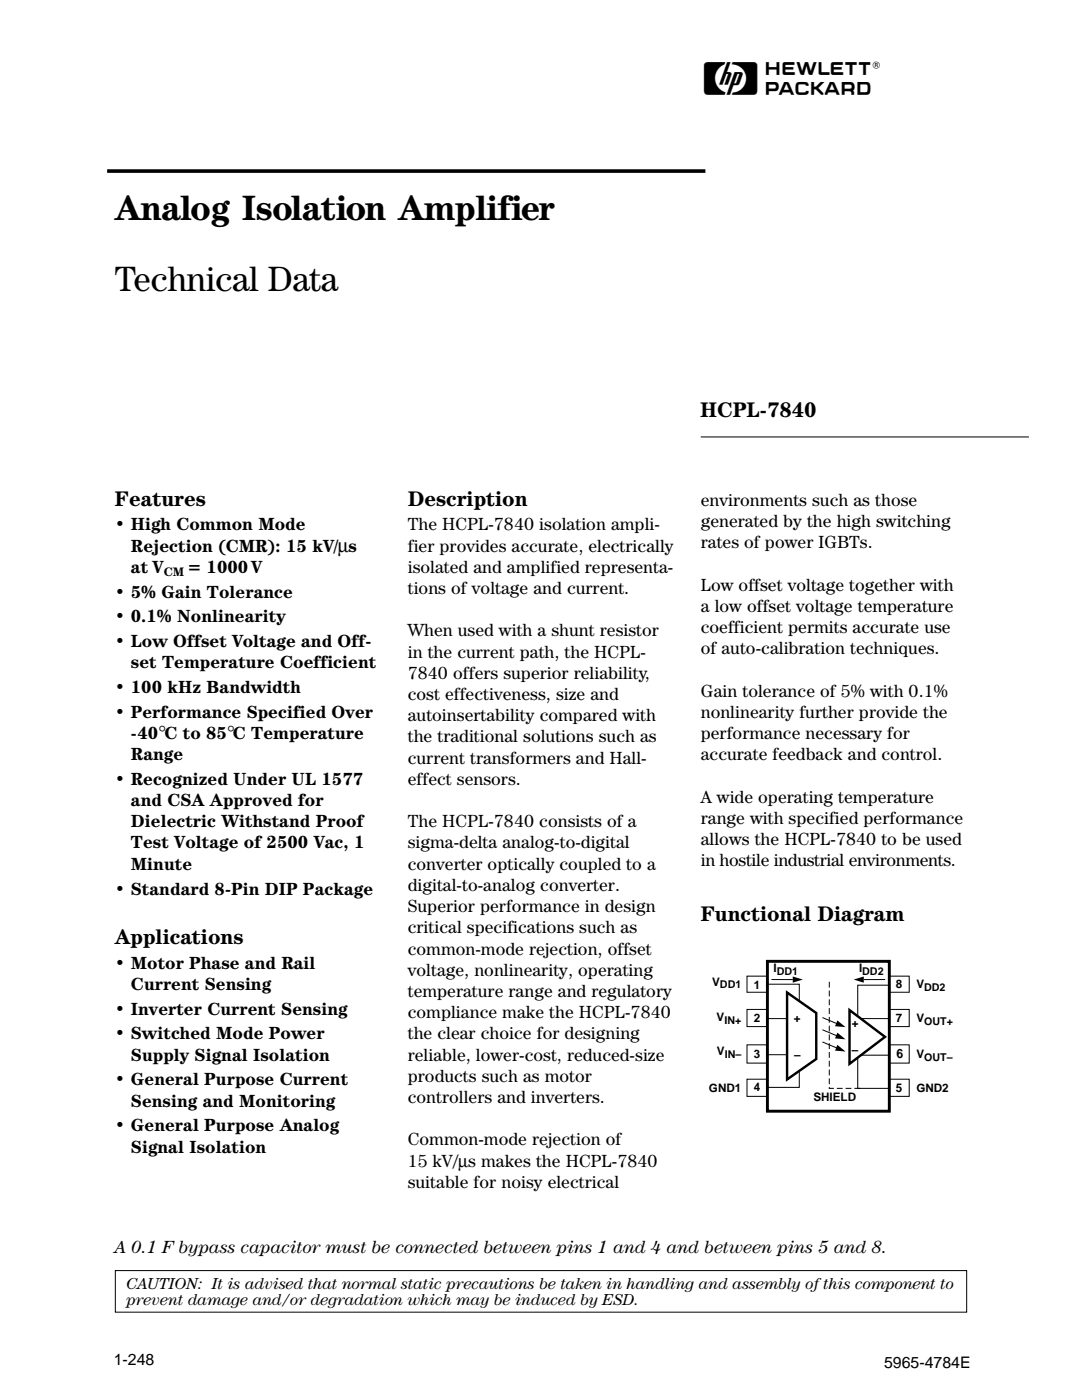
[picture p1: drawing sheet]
<svg xmlns="http://www.w3.org/2000/svg" width="216mm" height="279mm" viewBox="0 0 216 279" stroke-linecap="round" stroke-linejoin="round" font-family="sans-serif">
<defs><g id="words">
<g font-size="7.1">
<text x="139.9" y="17.8">H</text>
<text x="22.9" y="43.9">Analog Isolation Amplifier</text>
<text x="22.9" y="58">Technical Data</text>
</g>
<g font-size="4.2">
<text x="139.7" y="83.3">HCPL-7840</text>
<text x="22.9" y="100.9">Features</text>
<text x="81.4" y="100.9">Description</text>
<text x="139.8" y="183.8">Functional Diagram</text>
<text x="22.9" y="188.4">Applications</text>
</g>
<g font-size="3.5">
<text x="139.8" y="100.9">environments such as those</text>
<text x="22.9" y="105.8">• High Common Mode</text>
<text x="81.4" y="105.8">The HCPL-7840 isolation ampli-</text>
<text x="139.8" y="105.2">generated by the high switching</text>
<text x="26.1" y="110.1">Rejection (CMR): 15 kV/µs</text>
<text x="81.4" y="110.1">fier provides accurate, electrically</text>
<text x="139.8" y="109.4">rates of power IGBTs.</text>
<text x="22.9" y="119.3">• 5% Gain Tolerance</text>
<text x="26.1" y="114.3">at V</text>
<text x="37.4" y="114.3">= 1000 V</text>
<text x="81.4" y="114.3">isolated and amplified representa-</text>
<text x="81.4" y="118.5">tions of voltage and current.</text>
<text x="139.8" y="117.9">Low offset voltage together with</text>
<text x="22.9" y="124.2">• 0.1% Nonlinearity</text>
<text x="139.8" y="122.1">a low offset voltage temperature</text>
<text x="22.9" y="129.1">• Low Offset Voltage and Off-</text>
<text x="81.4" y="127">When used with a shunt resistor</text>
<text x="81.4" y="131.2">in the current path, the HCPL-</text>
<text x="139.8" y="126.3">coefficient permits accurate use</text>
<text x="139.8" y="130.6">of auto-calibration techniques.</text>
<text x="26.1" y="133.3">set Temperature Coefficient</text>
<text x="81.4" y="135.5">7840 offers superior reliability,</text>
<text x="22.9" y="138.3">• 100 kHz Bandwidth</text>
<text x="22.9" y="143.3">• Performance Specified Over</text>
<text x="81.4" y="139.7">cost effectiveness, size and</text>
<text x="81.4" y="143.9">autoinsertability compared with</text>
<text x="139.8" y="139">Gain tolerance of 5% with 0.1%</text>
<text x="139.8" y="143.3">nonlinearity further provide the</text>
<text x="26.1" y="147.5">-40°C to 85°C Temperature</text>
<text x="81.4" y="148.2">the traditional solutions such as</text>
<text x="139.8" y="147.5">performance necessary for</text>
<text x="26.1" y="151.7">Range</text>
<text x="81.4" y="152.4">current transformers and Hall-</text>
<text x="139.8" y="151.7">accurate feedback and control.</text>
<text x="22.9" y="156.6">• Recognized Under UL 1577</text>
<text x="26.1" y="160.9">and CSA Approved for</text>
<text x="81.4" y="156.6">effect sensors.</text>
<text x="139.8" y="160.2">A wide operating temperature</text>
<text x="26.1" y="165.1">Dielectric Withstand Proof</text>
<text x="81.4" y="165.1">The HCPL-7840 consists of a</text>
<text x="139.8" y="164.4">range with specified performance</text>
<text x="26.1" y="169.3">Test Voltage of 2500 Vac, 1</text>
<text x="26.1" y="173.6">Minute</text>
<text x="81.4" y="169.3">sigma-delta analog-to-digital</text>
<text x="81.4" y="173.6">converter optically coupled to a</text>
<text x="139.8" y="168.7">allows the HCPL-7840 to be used</text>
<text x="139.8" y="172.9">in hostile industrial environments.</text>
<text x="22.9" y="178.5">• Standard 8-Pin DIP Package</text>
<text x="81.4" y="177.8">digital-to-analog converter.</text>
<text x="81.4" y="182">Superior performance in design</text>
<text x="81.4" y="186.3">critical specifications such as</text>
<text x="81.4" y="190.5">common-mode rejection, offset</text>
<text x="22.9" y="193.3">• Motor Phase and Rail</text>
<text x="26.1" y="197.6">Current Sensing</text>
<text x="81.4" y="194.7">voltage, nonlinearity, operating</text>
<text x="22.9" y="202.5">• Inverter Current Sensing</text>
<text x="81.4" y="199">temperature range and regulatory</text>
<text x="81.4" y="203.2">compliance make the HCPL-7840</text>
<text x="22.9" y="207.4">• Switched Mode Power</text>
<text x="81.4" y="207.4">the clear choice for designing</text>
<text x="26.1" y="211.7">Supply Signal Isolation</text>
<text x="81.4" y="211.7">reliable, lower-cost, reduced-size</text>
<text x="81.4" y="215.9">products such as motor</text>
<text x="22.9" y="216.6">• General Purpose Current</text>
<text x="26.1" y="220.9">Sensing and Monitoring</text>
<text x="81.4" y="220.1">controllers and inverters.</text>
<text x="22.9" y="225.8">• General Purpose Analog</text>
<text x="26.1" y="230">Signal Isolation</text>
<text x="81.4" y="228.6">Common-mode rejection of</text>
<text x="81.4" y="232.8">15 kV/µs makes the HCPL-7840</text>
<text x="81.4" y="237.1">suitable for noisy electrical</text>
<text x="22.9" y="250.1">A 0.1 F bypass capacitor must be connected between pins 1 and 4 and between pins 5 and 8.</text>
</g>
<g font-size="3.2">
<text x="25.2" y="257.3">CAUTION: It is advised that normal static precautions be taken in handling and assembly of this component to</text>
<text x="25.2" y="260.4">prevent damage and/or degradation which may be induced by ESD.</text>
<text x="22.7" y="272.5">1-248</text>
<text x="176.4" y="272.9">5965-4784E</text>
</g>
<text font-size="2.6" x="178.9" y="211.2">6</text>
<text font-size="2.5" x="32.7" y="115">CM</text>
<g font-size="2.3">
<text x="142.1" y="196.7">V</text>
<text x="150.4" y="197.3">1</text>
<text x="154.3" y="194">I</text>
<text x="171.4" y="194">I</text>
<text x="178.8" y="197.1">8</text>
<text x="182.9" y="197.2">V</text>
<text x="143" y="203.7">V</text>
<text x="150.4" y="203.9">2</text>
<text x="178.8" y="203.9">7</text>
<text x="182.9" y="204">V</text>
<text x="158.4" y="204">+</text>
<text x="170" y="204.9">+</text>
<text x="143.1" y="210.6">V</text>
<text x="150.4" y="211.1">3</text>
<text x="158.4" y="211.3">–</text>
<text x="170" y="210.4">–</text>
<text x="182.9" y="211.2">V</text>
<text x="141.5" y="217.9">GND1</text>
<text x="150.4" y="217.7">4</text>
<text x="162.3" y="219.8">SHIELD</text>
<text x="178.8" y="217.9">5</text>
<text x="182.9" y="217.9">GND2</text>
</g>
<g font-size="2.1">
<text x="143.7" y="197.3">DD1</text>
<text x="155" y="194.5">DD1</text>
<text x="172.1" y="194.5">DD2</text>
<text x="184.4" y="197.8">DD2</text>
<text x="144.6" y="204.3">IN+</text>
<text x="184.4" y="204.6">OUT+</text>
<text x="144.6" y="211.2">IN–</text>
<text x="184.4" y="211.8">OUT–</text>
</g>
</g></defs>
<path d="M21.4 34.1h119.4" fill="none" stroke="#000" stroke-width=".72" stroke-linecap="butt"/>
<path d="M139.8 87.2h65.5M23 253.6h169.9v8.3h-169.9z" fill="none" stroke="#000" stroke-width=".2"/>
<g fill="#fff" stroke="#000" stroke-width=".2">
<path d="M149.1 194.8h32.3v3.2h-32.3z"/>
<path d="M149.1 201.5h32.3v3.4h-32.3z"/>
<path d="M149.1 215.4h32.3v3.4h-32.3z"/>
<path d="M149.1 208.5h32.3v3.7h-32.3z"/>
</g>
<path d="M153.1 191.9h24.4v29.9h-24.4z" fill="#fff" stroke="#000" stroke-width=".58"/>
<g fill="none" stroke="#000" stroke-width=".2">
<path d="M153.2 196.4h6.3v3.5M153.9 195.5h4.3M176.6 195.5h-4.2M177.4 196.6h-6.2v6.1M153.2 203.3h3.9M153.2 210.5h3.9M159.5 213.7v3.3h-6.3M164.1 203.1l2.9 1.2M164.1 205.5l2.9 1.2M164.1 207.9l2.9 1.3M171.2 211.1v6.1h6.3M171.9 203.3h5.6"/>
<path d="M171.9 210.6h5.6"/>
</g>
<path d="M157 198.1l5.9 4.1v9.1l-5.9 4.1zM169.5 201.6l7.1 5.3-7.1 5.4z" fill="none" stroke="#000" stroke-width=".49"/>
<path d="M158.2 194.9l2 .6-2 .6zM170.3 195.5l2.1-.6v1.2zM167.1 203.7l1.6 1.3-2.1-.2zM167.1 206.1l1.6 1.3-2.1-.2zM167.1 208.5l1.6 1.4-2.1-.2z" fill="#000"/>
<path d="M165.5 195.9v21.3h6.3" fill="none" stroke="#000" stroke-width=".2" stroke-dasharray="1.2 .6" stroke-linecap="butt"/>
<use href="#words"/>
</svg>
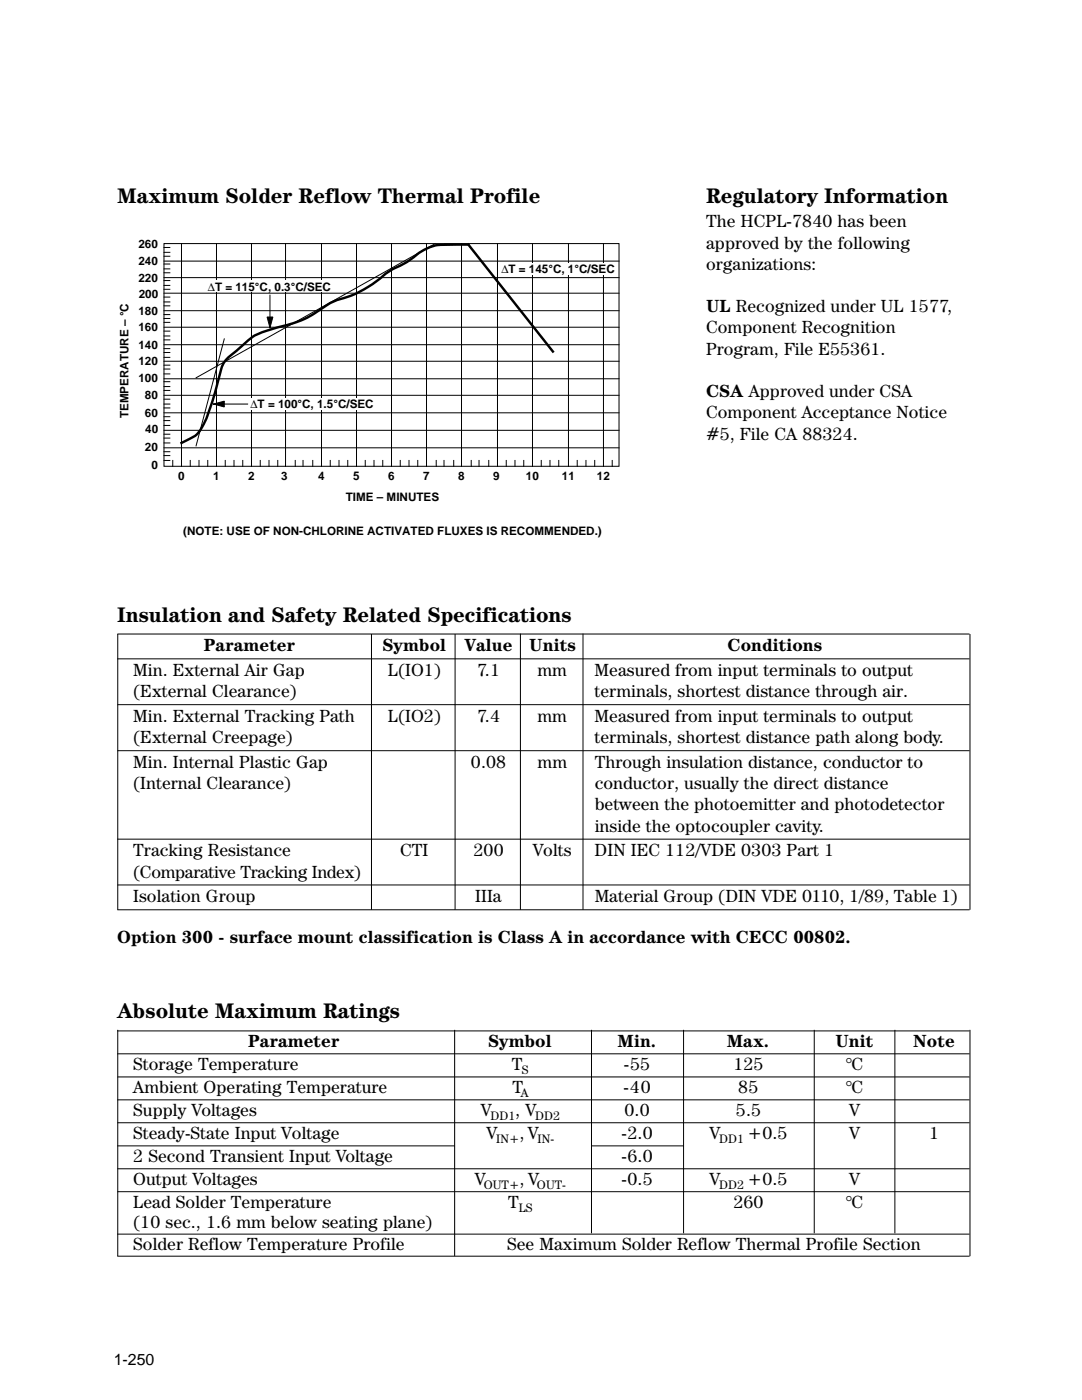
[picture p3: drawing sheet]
<svg xmlns="http://www.w3.org/2000/svg" width="216mm" height="279mm" viewBox="0 0 216 279" stroke-linecap="round" stroke-linejoin="round" font-family="sans-serif">
<defs><g id="words">
<g font-size="4.2">
<text x="23.4" y="40.4">Maximum Solder Reflow Thermal Profile</text>
<text x="140.9" y="40.4">Regulatory Information</text>
<text x="23.4" y="124">Insulation and Safety Related Specifications</text>
<text x="23.4" y="203.2">Absolute Maximum Ratings</text>
</g>
<g font-size="3.5">
<text x="140.9" y="45.4">The HCPL-7840 has been</text>
<text x="140.9" y="49.6">approved by the following</text>
<text x="140.9" y="53.8">organizations:</text>
<text x="140.9" y="62.3">UL Recognized under UL 1577,</text>
<text x="140.9" y="66.5">Component Recognition</text>
<text x="140.9" y="70.8">Program, File E55361.</text>
<text x="140.9" y="79.2">CSA Approved under CSA</text>
<text x="140.9" y="83.5">Component Acceptance Notice</text>
<text x="140.9" y="87.7">#5, File CA 88324.</text>
<text x="40.7" y="130">Parameter</text>
<text x="76.3" y="130">Symbol</text>
<text x="92.8" y="130">Value</text>
<text x="105.6" y="130">Units</text>
<text x="145.2" y="130">Conditions</text>
<text x="26.6" y="134.9">Min. External Air Gap</text>
<text x="77.4" y="134.9">L(IO1)</text>
<text x="95.2" y="134.9">7.1</text>
<text x="107.3" y="134.9">mm</text>
<text x="118.7" y="134.9">Measured from input terminals to output</text>
<text x="26.6" y="139.1">(External Clearance)</text>
<text x="118.7" y="139.1">terminals, shortest distance through air.</text>
<text x="26.6" y="144.1">Min. External Tracking Path</text>
<text x="26.6" y="148.3">(External Creepage)</text>
<text x="77.4" y="144.1">L(IO2)</text>
<text x="95.2" y="144.1">7.4</text>
<text x="107.3" y="144.1">mm</text>
<text x="118.7" y="144.1">Measured from input terminals to output</text>
<text x="118.7" y="148.3">terminals, shortest distance path along body.</text>
<text x="26.6" y="153.2">Min. Internal Plastic Gap</text>
<text x="94" y="153.2">0.08</text>
<text x="107.3" y="153.2">mm</text>
<text x="118.7" y="153.2">Through insulation distance, conductor to</text>
<text x="26.6" y="157.5">(Internal Clearance)</text>
<text x="118.7" y="161.7">between the photoemitter and photodetector</text>
<text x="118.7" y="157.5">conductor, usually the direct distance</text>
<text x="118.7" y="165.9">inside the optocoupler cavity.</text>
<text x="26.6" y="170.9">Tracking Resistance</text>
<text x="79.8" y="170.9">CTI</text>
<text x="94.5" y="170.9">200</text>
<text x="106.3" y="170.9">Volts</text>
<text x="118.7" y="170.9">DIN IEC 112/VDE 0303 Part 1</text>
<text x="26.6" y="175.1">(Comparative Tracking Index)</text>
<text x="26.6" y="180.1">Isolation Group</text>
<text x="94.8" y="180.1">IIIa</text>
<text x="118.7" y="180.1">Material Group (DIN VDE 0110, 1/89, Table 1)</text>
<text x="23.4" y="188.3">Option 300 - surface mount classification is Class A in accordance with CECC 00802.</text>
<text x="49.5" y="209">Parameter</text>
<text x="97.4" y="209">Symbol</text>
<text x="123.2" y="209">Min.</text>
<text x="145" y="209">Max.</text>
<text x="166.7" y="209">Unit</text>
<text x="182.2" y="209">Note</text>
<text x="26.6" y="213.6">Storage Temperature</text>
<text x="102.2" y="213.6">T</text>
<text x="124.5" y="213.6">-55</text>
<text x="146.3" y="213.6">125</text>
<text x="168.7" y="213.6">°C</text>
<text x="26.6" y="218.2">Ambient Operating Temperature</text>
<text x="102.2" y="218.2">T</text>
<text x="124.4" y="218.2">-40</text>
<text x="147.3" y="218.2">85</text>
<text x="168.7" y="218.2">°C</text>
<text x="26.6" y="222.8">Supply Voltages</text>
<text x="26.6" y="227.3">Steady-State Input Voltage</text>
<text x="95.9" y="222.8">V</text>
<text x="97.1" y="227.3">V</text>
<text x="102.8" y="222.8">, V</text>
<text x="103.6" y="227.3">, V</text>
<text x="124" y="227.3">-2.0</text>
<text x="124.6" y="222.8">0.0</text>
<text x="141.6" y="227.3">V</text>
<text x="146.9" y="222.8">5.5</text>
<text x="149.2" y="227.3">+0.5</text>
<text x="169.4" y="222.8">V</text>
<text x="169.4" y="227.3">V</text>
<text x="185.4" y="227.3">1</text>
<text x="26.6" y="231.9">2 Second Transient Input Voltage</text>
<text x="124" y="231.9">-6.0</text>
<text x="26.6" y="236.5">Output Voltages</text>
<text x="94.7" y="236.5">V</text>
<text x="103.6" y="236.5">, V</text>
<text x="124" y="236.5">-0.5</text>
<text x="141.6" y="236.5">V</text>
<text x="149.2" y="236.5">+0.5</text>
<text x="169.4" y="236.5">V</text>
<text x="26.6" y="241.1">Lead Solder Temperature</text>
<text x="26.6" y="245">(10 sec., 1.6 mm below seating plane)</text>
<text x="101.4" y="241.1">T</text>
<text x="146.3" y="241.1">260</text>
<text x="168.7" y="241.1">°C</text>
<text x="26.6" y="249.6">Solder Reflow Temperature Profile</text>
<text x="101.2" y="249.6">See Maximum Solder Reflow Thermal Profile Section</text>
</g>
<text font-size="3.2" x="22.7" y="272.5">1-250</text>
<g font-size="2.5">
<text x="104.1" y="214.3">S</text>
<text x="103.9" y="218.9">A</text>
<text x="97.9" y="223.5">DD1</text>
<text x="106.8" y="223.5">DD2</text>
<text x="99" y="228">IN+</text>
<text x="107.3" y="228">IN-</text>
<text x="143.5" y="228">DD1</text>
<text x="96.5" y="237.2">OUT+</text>
<text x="107.1" y="237.2">OUT-</text>
<text x="143.5" y="237.2">DD2</text>
<text x="103.5" y="241.8">LS</text>
</g>
<g font-size="2.3">
<text x="27.6" y="52.9">240</text>
<text x="27.6" y="49.6">260</text>
<text x="27.6" y="56.2">220</text>
<text x="27.7" y="59.5">200</text>
<text x="41.5" y="58">∆T = 115°C, 0.3°C/SEC</text>
<text x="100" y="54.5">∆T = 145°C, 1°C/SEC</text>
<text x="27.6" y="62.8">180</text>
<text x="27.6" y="66.1">160</text>
<text x="27.6" y="69.6">140</text>
<text x="27.6" y="72.9">120</text>
<text x="27.6" y="76.2">100</text>
<text x="25.6" y="83.5" transform="rotate(-90 25.6 83.5)">TEMPERATURE – °C</text>
<text x="28.9" y="79.7">80</text>
<text x="28.9" y="83.2">60</text>
<text x="50" y="81.5">∆T = 100°C, 1.5°C/SEC</text>
<text x="28.9" y="90">20</text>
<text x="29" y="86.5">40</text>
<text x="30.2" y="93.6">0</text>
<text x="35.6" y="95.8">0</text>
<text x="42.6" y="95.8">1</text>
<text x="49.5" y="95.8">2</text>
<text x="56.1" y="95.8">3</text>
<text x="63.5" y="95.8">4</text>
<text x="70.5" y="95.8">5</text>
<text x="77.5" y="95.8">6</text>
<text x="84.5" y="95.8">7</text>
<text x="91.4" y="95.8">8</text>
<text x="98.4" y="95.8">9</text>
<text x="105" y="95.8">10</text>
<text x="112.1" y="95.8">11</text>
<text x="119.1" y="95.8">12</text>
<text x="69" y="100">TIME – MINUTES</text>
<text x="36.5" y="106.7">(NOTE: USE OF NON-CHLORINE ACTIVATED FLUXES IS RECOMMENDED.)</text>
</g>
</g></defs>
<g fill="none" stroke="#000" stroke-width=".2">
<path d="M32.7 48.6h90.8v44.5h-90.8zM32.7 52.1h90.8M32.7 52.7h1.2M32.7 53.7h1.2M32.7 54.4h1.2M32.7 55.4h90.8M32.7 56h1.2M32.7 57h1.2M32.7 57.7h1.2M32.7 58.5h90.8M32.7 59.3h1.2M36.2 48.6v44.5"/>
<path d="M43.2 48.6v44.5M50.2 48.6v44.5M57 48.6v44.5M64.2 48.6v44.5M71.1 48.6v44.5M78.1 48.6v44.5M85.1 48.6v44.5M86.9 48.6l-47.8 26.8M92.1 48.6v44.5M99.3 48.6v44.5M106.3 48.6v44.5M113.4 48.6v44.5"/>
<path d="M120.4 48.6v44.5M32.7 60.3h1.2M32.7 61h1.2M32.7 62h90.8M32.7 62.8h1.2M32.7 63.6h1.2M32.7 64.3h1.2M32.7 65.3h90.8M32.7 66.1h1.2M32.7 67.1h1.2M32.7 67.8h1.2M32.7 68.8h90.8"/>
<path d="M32.7 69.6h1.2M32.7 70.4h1.2M32.7 71.3h1.2M32.7 72.1h90.8M32.7 72.9h1.2M32.7 73.7h1.2M32.7 74.6h1.2M32.7 75.6h90.8M32.7 76.2h1.2M32.7 77.1h1.2M32.7 77.9h1.2M32.7 78.9h90.8"/>
<path d="M32.7 79.7h1.2M44.8 67.6l-5.7 21.4M32.7 80.6h1.2M32.7 81.4h1.2M32.7 82.4h90.8M32.7 83.2h1.2M32.7 83.9h1.2M32.7 84.9h1.2M32.7 85.9h90.8M32.7 86.7h1.2M32.7 87.4h1.2M32.7 88.4h1.2"/>
<path d="M32.7 89.4h90.8M32.7 90.1h1.2M32.7 90.9h1.2M32.7 91.9h1.2M34.5 91.9v1.2M38 91.9v1.2M39.7 91.9v1.2M41.5 91.9v1.2M44.9 91.9v1.2M46.7 91.9v1.2M48.4 91.9v1.2M51.9 91.9v1.2"/>
<path d="M53.7 91.9v1.2M55.4 91.9v1.2M58.9 91.9v1.2M60.5 91.9v1.2M62.4 91.9v1.2M65.9 91.9v1.2M67.6 91.9v1.2M69.4 91.9v1.2M72.9 91.9v1.2M74.6 91.9v1.2M76.4 91.9v1.2M79.9 91.9v1.2"/>
<path d="M81.6 91.9v1.2M83.4 91.9v1.2M87 91.9v1.2M88.6 91.9v1.2M90.5 91.9v1.2M94 91.9v1.2M95.6 91.9v1.2M97.5 91.9v1.2M101 91.9v1.2M102.8 91.9v1.2M104.5 91.9v1.2M108 91.9v1.2"/>
<path d="M109.7 91.9v1.2M111.5 91.9v1.2M115.2 91.9v1.2M116.9 91.9v1.2M118.7 91.9v1.2M122.2 91.9v1.2"/>
</g>
<path d="M110.3 70.2l-16.9-21.4h-3.3a10 10 0 0 0-8.1 2.9l-1.9 1.2a14.9 14.9 0 0 0-5 3.3 21.7 21.7 0 0 1-8.1 3.8l-.9 .4a34.1 34.1 0 0 1-7.2 4l-.5 .1a46.9 46.9 0 0 0-7.7 2.5l-3.1 2.6a10.9 10.9 0 0 0-3.3 3.5l-.4 1.5a48.6 48.6 0 0 1-3.6 10.7 4.8 4.8 0 0 1-2.9 2.5l-1.2 .6" fill="none" stroke="#000" stroke-width=".49"/>
<path d="M39.9 56h24.4v2.3h-24.4z" fill="#fff"/>
<path d="M53.3 63.3h1.2l-.6 2.1zM42.6 80.6l2.2-.5v1.1z" fill="#000" stroke="#000" stroke-width=".2"/>
<path d="M53.9 58.9v4.6M44.8 80.6h4.6" fill="none" stroke="#000" stroke-width=".2"/>
<g fill="#fff">
<path d="M49.8 79.5h24.4v2.3h-24.4z"/>
<path d="M99.5 52.5h22.3v2.3h-22.3z"/>
</g>
<g fill="none" stroke="#000" stroke-width=".2">
<path d="M32.7 49.4h1.2M32.7 50.4h1.2M32.7 51.1h1.2M23.4 126.5h170.1M23.4 131.5h170.1M23.5 126.5v55.1M74.1 126.5v55.1M90.8 126.5v55.1M103.8 126.4v55.2M116.3 126.4v55.2M193.5 126.5v55.1M23.4 140.6h170.1"/>
<path d="M23.4 149.8h170.1M23.4 167.5h170.1M23.4 176.6h170.1M23.4 181.6h170.1M23.4 205.7h170.1M23.4 210.3h170.1M23.4 214.9h170.1M23.4 219.5h170.1M23.5 205.5v45.2M23.4 224.1h170.1M23.4 228.7h170.1M23.4 233.3h170.1"/>
<path d="M23.4 237.8h170.1M23.4 246.3h170.1M23.4 250.7h170.1"/>
</g>
<g fill="#fff">
<path d="M90.8 228.2h27.2v1.1h-27.2z"/>
<path d="M136.5 228.2h56.9v1h-56.9z"/>
</g>
<path d="M90.7 205.5v45.2M118 205.5v40.6M136.4 205.5v40.6M162.5 205.5v40.6M178.6 205.5v40.6M193.5 205.5v45.2" fill="none" stroke="#000" stroke-width=".2"/>
<use href="#words"/>
</svg>
